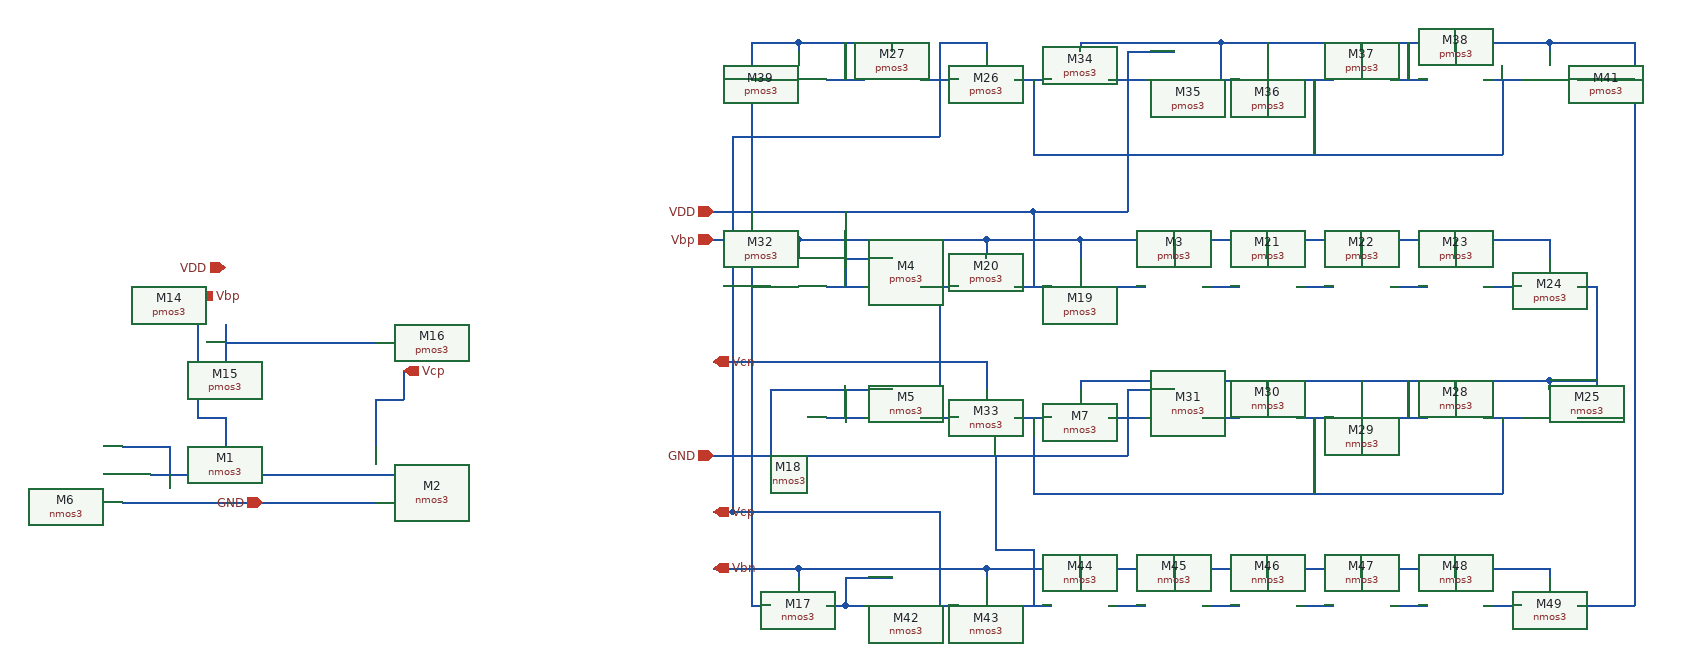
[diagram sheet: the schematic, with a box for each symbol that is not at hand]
v {xschem version=3.4.3 file_version=1.2
}
G {}
K {}
V {}
S {}
E {}
N -270 -190 -180 -190 {
lab=#net1}
N -310 -210 -310 -170 {
lab=#net1}
N -310 -190 -270 -190 {
lab=#net1}
N -340 -240 -340 -140 {
lab=Vbp}
N -340 -140 -340 -110 {
lab=Vbp}
N -340 -110 -310 -110 {
lab=Vbp}
N -120 -160 -120 -130 {
lab=Vcp}
N -150 -130 -120 -130 {
lab=Vcp}
N -180 -190 -150 -190 {
lab=#net1}
N -120 -50 -70 -50 {
lab=Vbn}
N -150 -130 -150 -80 {
lab=Vcp}
N -310 -110 -310 -80 {
lab=Vbp}
N -370 -80 -370 -50 {
lab=Vbn}
N -420 -80 -370 -80 {
lab=Vbn}
N -390 -50 -340 -50 {
lab=Vbn}
N -340 -50 -120 -50 {
lab=Vbn}
N -420 -20 -310 -20 {
lab=GND}
N -310 -20 -270 -20 {
lab=GND}
N -270 -20 -150 -20 {
lab=GND}
N 530 -250 570 -250 {
lab=VDD}
N 550 -310 550 -250 {
lab=VDD}
N 500 -300 500 -280 {
lab=Vbp}
N 500 -300 600 -300 {
lab=Vbp}
N 600 -300 1100 -300 {
lab=Vbp}
N 1100 -300 1100 -280 {
lab=Vbp}
N 1000 -300 1000 -280 {
lab=Vbp}
N 900 -300 900 -280 {
lab=Vbp}
N 800 -300 800 -280 {
lab=Vbp}
N 700 -300 700 -280 {
lab=Vbp}
N 600 -300 600 -280 {
lab=Vbp}
N 1130 -250 1150 -250 {
lab=#net5}
N 800 -150 800 -140 {
lab=#net6}
N 730 -110 770 -110 {
lab=#net7}
N 830 -110 870 -110 {
lab=#net8}
N 900 -150 900 -140 {
lab=#net6}
N 1000 -150 1000 -140 {
lab=#net6}
N 1100 -150 1100 -140 {
lab=#net6}
N 930 -110 970 -110 {
lab=#net9}
N 550 -330 550 -310 {
lab=VDD}
N 210 -330 550 -330 {
lab=VDD}
N 650 -30 1050 -30 {
lab=#net8}
N 630 -250 670 -250 {
lab=#net10}
N 730 -250 770 -250 {
lab=#net11}
N 830 -250 870 -250 {
lab=#net12}
N 930 -250 970 -250 {
lab=#net13}
N 1030 -250 1070 -250 {
lab=#net14}
N 470 -170 500 -170 {
lab=Vcn}
N 210 -170 470 -170 {
lab=Vcn}
N 630 -470 670 -470 {
lab=#net15}
N 730 -470 770 -470 {
lab=#net16}
N 830 -470 870 -470 {
lab=#net15}
N 930 -470 970 -470 {
lab=#net16}
N 1100 -510 1100 -500 {
lab=#net16}
N 1000 -510 1000 -500 {
lab=#net16}
N 900 -510 900 -500 {
lab=#net16}
N 800 -510 800 -500 {
lab=#net16}
N 750 -510 750 -470 {
lab=#net16}
N 950 -510 950 -470 {
lab=#net16}
N 1050 -470 1050 -390 {
lab=#net15}
N 1030 -110 1070 -110 {
lab=#net8}
N 500 -170 500 -140 {
lab=Vcn}
N 430 -250 470 -250 {
lab=Vcn}
N 330 -250 370 -250 {
lab=VDD}
N 350 -330 350 -250 {
lab=VDD}
N 350 60 400 60 {
lab=#net17}
N 350 60 350 90 {
lab=#net17}
N 330 90 350 90 {
lab=#net17}
N 350 90 370 90 {
lab=#net17}
N 350 -280 400 -280 {
lab=VDD}
N 1100 50 1100 60 {
lab=Vbn}
N 500 50 1100 50 {
lab=Vbn}
N 500 50 500 60 {
lab=Vbn}
N 600 50 600 60 {
lab=Vbn}
N 700 50 700 60 {
lab=Vbn}
N 800 50 800 60 {
lab=Vbn}
N 900 50 900 60 {
lab=Vbn}
N 1000 50 1000 60 {
lab=Vbn}
N 530 90 570 90 {
lab=GND}
N 550 30 550 90 {
lab=GND}
N 630 90 670 90 {
lab=#net18}
N 730 90 770 90 {
lab=#net19}
N 830 90 870 90 {
lab=#net20}
N 930 90 970 90 {
lab=#net21}
N 1030 90 1070 90 {
lab=#net22}
N 430 90 470 90 {
lab=Vcp}
N 300 50 300 60 {
lab=Vbn}
N 300 50 500 50 {
lab=Vbn}
N 300 -300 300 -280 {
lab=Vbp}
N 300 -300 500 -300 {
lab=Vbp}
N 270 -300 300 -300 {
lab=Vbp}
N 450 30 450 90 {
lab=Vcp}
N 250 -300 270 -300 {
lab=Vbp}
N 250 -300 250 90 {
lab=Vbp}
N 250 90 270 90 {
lab=Vbp}
N 250 -250 270 -250 {
lab=Vbp}
N 430 -110 470 -110 {
lab=Vcn}
N 270 -140 300 -140 {
lab=GND}
N 270 -140 270 -110 {
lab=GND}
N 270 -110 270 -70 {
lab=GND}
N 330 -110 370 -110 {
lab=GND}
N 350 -140 350 -110 {
lab=GND}
N 1030 -470 1070 -470 {
lab=#net15}
N 530 -470 570 -470 {
lab=Vcp}
N 500 -510 500 -500 {
lab=VDD}
N 300 -510 300 -500 {
lab=VDD}
N 400 -510 400 -500 {
lab=VDD}
N 430 -470 470 -470 {
lab=VDD}
N 330 -470 370 -470 {
lab=VDD}
N 350 -510 350 -470 {
lab=VDD}
N 250 -510 300 -510 {
lab=VDD}
N 250 -510 250 -330 {
lab=VDD}
N 250 -470 270 -470 {
lab=VDD}
N 850 -470 850 -390 {
lab=#net15}
N 1130 90 1190 90 {
lab=#net16}
N 1190 -510 1190 90 {
lab=#net16}
N 1100 -510 1190 -510 {
lab=#net16}
N 210 50 300 50 {
lab=Vbn}
N 210 -300 250 -300 {
lab=Vbp}
N 450 -10 450 30 {
lab=Vcp}
N 230 -10 450 -10 {
lab=Vcp}
N 230 -410 230 -10 {
lab=Vcp}
N 450 -470 450 -410 {
lab=Vcp}
N 210 -10 230 -10 {
lab=Vcp}
N 1130 -110 1150 -110 {
lab=#net23}
N 300 -140 400 -140 {
lab=GND}
N 450 -250 450 -170 {
lab=Vcn}
N 450 -170 450 -110 {
lab=Vcn}
N 530 -110 570 -110 {
lab=#net24}
N 630 -110 670 -110 {
lab=#net25}
N 600 -150 600 -140 {
lab=#net6}
N 650 -140 700 -140 {
lab=#net25}
N 650 -140 650 -110 {
lab=#net25}
N 600 -150 1100 -150 {
lab=#net6}
N 1150 -250 1150 -110 {}
N 1100 -150 1150 -150 {}
N 1050 -110 1050 -30 {}
N 850 -110 850 -30 {}
N 550 -110 550 -30 {}
N 550 -30 650 -30 {}
N 650 -110 650 -70 {}
N 210 -70 650 -70 {}
N 950 -150 950 -110 {}
N 750 -150 750 -110 {}
N 1130 -470 1190 -470 {}
N 230 -410 450 -410 {}
N 300 -510 400 -510 {}
N 450 -510 450 -470 {}
N 450 -510 500 -510 {}
N 750 -510 1100 -510 {}
N 600 -510 600 -500 {}
N 600 -510 750 -510 {}
N 650 -500 700 -500 {}
N 650 -500 650 -470 {}
N 550 -470 550 -390 {}
N 550 -330 650 -330 {}
N 510 30 550 30 {}
N 510 -70 510 30 {}
N 550 -390 1050 -390 {}
N 650 -470 650 -330 {}
C {devices/iopin.sym} -70 -50 0 0 {name=p6 lab=Vbn}
C {devices/iopin.sym} -310 -270 3 0 {name=p2 lab=VDD}
C {devices/iopin.sym} -270 -20 1 0 {name=p3 lab=GND}
C {devices/opin.sym} -340 -240 2 0 {name=p1 lab=Vbp}
C {madvlsi/nmos3.sym} -150 -50 0 0 {name=M2
L=0.5
W=12
body=GND
nf=1
mult=1
ad="'int((nf+1)/2) * W/nf * 0.29'" 
pd="'2*int((nf+1)/2) * (W/nf + 0.29)'"
as="'int((nf+2)/2) * W/nf * 0.29'" 
ps="'2*int((nf+2)/2) * (W/nf + 0.29)'"
nrd="'0.29 / W'" nrs="'0.29 / W'"
sa=0 sb=0 sd=0
model=nfet_01v8
spiceprefix=X
}
C {madvlsi/nmos3.sym} -310 -50 0 0 {name=M1
L=0.5
W=12
body=GND
nf=1
mult=1/5
ad="'int((nf+1)/2) * W/nf * 0.29'" 
pd="'2*int((nf+1)/2) * (W/nf + 0.29)'"
as="'int((nf+2)/2) * W/nf * 0.29'" 
ps="'2*int((nf+2)/2) * (W/nf + 0.29)'"
nrd="'0.29 / W'" nrs="'0.29 / W'"
sa=0 sb=0 sd=0
model=nfet_01v8
spiceprefix=X
}
C {devices/opin.sym} -120 -160 0 0 {name=p7 lab=Vcp}
C {madvlsi/pmos3.sym} -310 -240 0 0 {name=M14
L=0.5
W=12
body=VDD
nf=1
mult=1
ad="'int((nf+1)/2) * W/nf * 0.29'" 
pd="'2*int((nf+1)/2) * (W/nf + 0.29)'"
as="'int((nf+2)/2) * W/nf * 0.29'" 
ps="'2*int((nf+2)/2) * (W/nf + 0.29)'"
nrd="'0.29 / W'" nrs="'0.29 / W'"
sa=0 sb=0 sd=0
model=pfet_01v8
spiceprefix=X
}
C {madvlsi/pmos3.sym} -310 -140 0 0 {name=M15
L=0.5
W=12
body=VDD
nf=1
mult=3
ad="'int((nf+1)/2) * W/nf * 0.29'" 
pd="'2*int((nf+1)/2) * (W/nf + 0.29)'"
as="'int((nf+2)/2) * W/nf * 0.29'" 
ps="'2*int((nf+2)/2) * (W/nf + 0.29)'"
nrd="'0.29 / W'" nrs="'0.29 / W'"
sa=0 sb=0 sd=0
model=pfet_01v8
spiceprefix=X
}
C {madvlsi/pmos3.sym} -150 -160 0 1 {name=M16
L=0.5
W=12
body=VDD
nf=1
mult=1
ad="'int((nf+1)/2) * W/nf * 0.29'" 
pd="'2*int((nf+1)/2) * (W/nf + 0.29)'"
as="'int((nf+2)/2) * W/nf * 0.29'" 
ps="'2*int((nf+2)/2) * (W/nf + 0.29)'"
nrd="'0.29 / W'" nrs="'0.29 / W'"
sa=0 sb=0 sd=0
model=pfet_01v8
spiceprefix=X
}
C {madvlsi/nmos3.sym} -420 -50 0 1 {name=M6
L=0.5
W=12
body=GND
nf=1
mult=1
ad="'int((nf+1)/2) * W/nf * 0.29'" 
pd="'2*int((nf+1)/2) * (W/nf + 0.29)'"
as="'int((nf+2)/2) * W/nf * 0.29'" 
ps="'2*int((nf+2)/2) * (W/nf + 0.29)'"
nrd="'0.29 / W'" nrs="'0.29 / W'"
sa=0 sb=0 sd=0
model=nfet_01v8
spiceprefix=X
}
C {madvlsi/pmos3.sym} 700 -250 1 0 {name=M3
L=0.5
W=12
body=VDD
nf=1
mult=1
ad="'int((nf+1)/2) * W/nf * 0.29'" 
pd="'2*int((nf+1)/2) * (W/nf + 0.29)'"
as="'int((nf+2)/2) * W/nf * 0.29'" 
ps="'2*int((nf+2)/2) * (W/nf + 0.29)'"
nrd="'0.29 / W'" nrs="'0.29 / W'"
sa=0 sb=0 sd=0
model=pfet_01v8
spiceprefix=X
}
C {madvlsi/pmos3.sym} 600 -250 1 0 {name=M19
L=0.5
W=12
body=VDD
nf=1
mult=1
ad="'int((nf+1)/2) * W/nf * 0.29'" 
pd="'2*int((nf+1)/2) * (W/nf + 0.29)'"
as="'int((nf+2)/2) * W/nf * 0.29'" 
ps="'2*int((nf+2)/2) * (W/nf + 0.29)'"
nrd="'0.29 / W'" nrs="'0.29 / W'"
sa=0 sb=0 sd=0
model=pfet_01v8
spiceprefix=X
}
C {madvlsi/pmos3.sym} 500 -250 1 0 {name=M20
L=0.5
W=12
body=VDD
nf=1
mult=1
ad="'int((nf+1)/2) * W/nf * 0.29'" 
pd="'2*int((nf+1)/2) * (W/nf + 0.29)'"
as="'int((nf+2)/2) * W/nf * 0.29'" 
ps="'2*int((nf+2)/2) * (W/nf + 0.29)'"
nrd="'0.29 / W'" nrs="'0.29 / W'"
sa=0 sb=0 sd=0
model=pfet_01v8
spiceprefix=X
}
C {madvlsi/pmos3.sym} 800 -250 1 0 {name=M21
L=0.5
W=12
body=VDD
nf=1
mult=1
ad="'int((nf+1)/2) * W/nf * 0.29'" 
pd="'2*int((nf+1)/2) * (W/nf + 0.29)'"
as="'int((nf+2)/2) * W/nf * 0.29'" 
ps="'2*int((nf+2)/2) * (W/nf + 0.29)'"
nrd="'0.29 / W'" nrs="'0.29 / W'"
sa=0 sb=0 sd=0
model=pfet_01v8
spiceprefix=X
}
C {madvlsi/pmos3.sym} 900 -250 1 0 {name=M22
L=0.5
W=12
body=VDD
nf=1
mult=1
ad="'int((nf+1)/2) * W/nf * 0.29'" 
pd="'2*int((nf+1)/2) * (W/nf + 0.29)'"
as="'int((nf+2)/2) * W/nf * 0.29'" 
ps="'2*int((nf+2)/2) * (W/nf + 0.29)'"
nrd="'0.29 / W'" nrs="'0.29 / W'"
sa=0 sb=0 sd=0
model=pfet_01v8
spiceprefix=X
}
C {madvlsi/pmos3.sym} 1000 -250 1 0 {name=M23
L=0.5
W=12
body=VDD
nf=1
mult=1
ad="'int((nf+1)/2) * W/nf * 0.29'" 
pd="'2*int((nf+1)/2) * (W/nf + 0.29)'"
as="'int((nf+2)/2) * W/nf * 0.29'" 
ps="'2*int((nf+2)/2) * (W/nf + 0.29)'"
nrd="'0.29 / W'" nrs="'0.29 / W'"
sa=0 sb=0 sd=0
model=pfet_01v8
spiceprefix=X
}
C {madvlsi/pmos3.sym} 1100 -250 1 0 {name=M24
L=0.5
W=12
body=VDD
nf=1
mult=1
ad="'int((nf+1)/2) * W/nf * 0.29'" 
pd="'2*int((nf+1)/2) * (W/nf + 0.29)'"
as="'int((nf+2)/2) * W/nf * 0.29'" 
ps="'2*int((nf+2)/2) * (W/nf + 0.29)'"
nrd="'0.29 / W'" nrs="'0.29 / W'"
sa=0 sb=0 sd=0
model=pfet_01v8
spiceprefix=X
}
C {madvlsi/nmos3.sym} 1100 -110 1 0 {name=M25
L=0.5
W=12
body=GND
nf=1
mult=1
ad="'int((nf+1)/2) * W/nf * 0.29'" 
pd="'2*int((nf+1)/2) * (W/nf + 0.29)'"
as="'int((nf+2)/2) * W/nf * 0.29'" 
ps="'2*int((nf+2)/2) * (W/nf + 0.29)'"
nrd="'0.29 / W'" nrs="'0.29 / W'"
sa=0 sb=0 sd=0
model=nfet_01v8
spiceprefix=X
}
C {madvlsi/nmos3.sym} 1000 -110 1 0 {name=M28
L=0.5
W=12
body=GND
nf=1
mult=1
ad="'int((nf+1)/2) * W/nf * 0.29'" 
pd="'2*int((nf+1)/2) * (W/nf + 0.29)'"
as="'int((nf+2)/2) * W/nf * 0.29'" 
ps="'2*int((nf+2)/2) * (W/nf + 0.29)'"
nrd="'0.29 / W'" nrs="'0.29 / W'"
sa=0 sb=0 sd=0
model=nfet_01v8
spiceprefix=X
}
C {madvlsi/nmos3.sym} 900 -110 1 0 {name=M29
L=0.5
W=12
body=GND
nf=1
mult=1
ad="'int((nf+1)/2) * W/nf * 0.29'" 
pd="'2*int((nf+1)/2) * (W/nf + 0.29)'"
as="'int((nf+2)/2) * W/nf * 0.29'" 
ps="'2*int((nf+2)/2) * (W/nf + 0.29)'"
nrd="'0.29 / W'" nrs="'0.29 / W'"
sa=0 sb=0 sd=0
model=nfet_01v8
spiceprefix=X
}
C {madvlsi/nmos3.sym} 800 -110 1 0 {name=M30
L=0.5
W=12
body=GND
nf=1
mult=1
ad="'int((nf+1)/2) * W/nf * 0.29'" 
pd="'2*int((nf+1)/2) * (W/nf + 0.29)'"
as="'int((nf+2)/2) * W/nf * 0.29'" 
ps="'2*int((nf+2)/2) * (W/nf + 0.29)'"
nrd="'0.29 / W'" nrs="'0.29 / W'"
sa=0 sb=0 sd=0
model=nfet_01v8
spiceprefix=X
}
C {madvlsi/nmos3.sym} 700 -110 1 0 {name=M31
L=0.5
W=12
body=GND
nf=1
mult=1
ad="'int((nf+1)/2) * W/nf * 0.29'" 
pd="'2*int((nf+1)/2) * (W/nf + 0.29)'"
as="'int((nf+2)/2) * W/nf * 0.29'" 
ps="'2*int((nf+2)/2) * (W/nf + 0.29)'"
nrd="'0.29 / W'" nrs="'0.29 / W'"
sa=0 sb=0 sd=0
model=nfet_01v8
spiceprefix=X
}
C {devices/iopin.sym} 210 -330 2 0 {name=p8 lab=VDD}
C {madvlsi/pmos3.sym} 300 -250 1 0 {name=M32
L=0.5
W=12
body=VDD
nf=1
mult=1
ad="'int((nf+1)/2) * W/nf * 0.29'" 
pd="'2*int((nf+1)/2) * (W/nf + 0.29)'"
as="'int((nf+2)/2) * W/nf * 0.29'" 
ps="'2*int((nf+2)/2) * (W/nf + 0.29)'"
nrd="'0.29 / W'" nrs="'0.29 / W'"
sa=0 sb=0 sd=0
model=pfet_01v8
spiceprefix=X
}
C {madvlsi/nmos3.sym} 500 -110 1 0 {name=M33
L=0.5
W=12
body=GND
nf=1
mult=1
ad="'int((nf+1)/2) * W/nf * 0.29'" 
pd="'2*int((nf+1)/2) * (W/nf + 0.29)'"
as="'int((nf+2)/2) * W/nf * 0.29'" 
ps="'2*int((nf+2)/2) * (W/nf + 0.29)'"
nrd="'0.29 / W'" nrs="'0.29 / W'"
sa=0 sb=0 sd=0
model=nfet_01v8
spiceprefix=X
}
C {devices/opin.sym} 210 -170 2 0 {name=p9 lab=Vcn}
C {madvlsi/pmos3.sym} 600 -470 1 0 {name=M34
L=0.5
W=12
body=VDD
nf=1
mult=1
ad="'int((nf+1)/2) * W/nf * 0.29'" 
pd="'2*int((nf+1)/2) * (W/nf + 0.29)'"
as="'int((nf+2)/2) * W/nf * 0.29'" 
ps="'2*int((nf+2)/2) * (W/nf + 0.29)'"
nrd="'0.29 / W'" nrs="'0.29 / W'"
sa=0 sb=0 sd=0
model=pfet_01v8
spiceprefix=X
}
C {madvlsi/pmos3.sym} 700 -470 1 0 {name=M35
L=0.5
W=12
body=VDD
nf=1
mult=1
ad="'int((nf+1)/2) * W/nf * 0.29'" 
pd="'2*int((nf+1)/2) * (W/nf + 0.29)'"
as="'int((nf+2)/2) * W/nf * 0.29'" 
ps="'2*int((nf+2)/2) * (W/nf + 0.29)'"
nrd="'0.29 / W'" nrs="'0.29 / W'"
sa=0 sb=0 sd=0
model=pfet_01v8
spiceprefix=X
}
C {madvlsi/pmos3.sym} 800 -470 1 0 {name=M36
L=0.5
W=12
body=VDD
nf=1
mult=1
ad="'int((nf+1)/2) * W/nf * 0.29'" 
pd="'2*int((nf+1)/2) * (W/nf + 0.29)'"
as="'int((nf+2)/2) * W/nf * 0.29'" 
ps="'2*int((nf+2)/2) * (W/nf + 0.29)'"
nrd="'0.29 / W'" nrs="'0.29 / W'"
sa=0 sb=0 sd=0
model=pfet_01v8
spiceprefix=X
}
C {madvlsi/pmos3.sym} 900 -470 1 0 {name=M37
L=0.5
W=12
body=VDD
nf=1
mult=1
ad="'int((nf+1)/2) * W/nf * 0.29'" 
pd="'2*int((nf+1)/2) * (W/nf + 0.29)'"
as="'int((nf+2)/2) * W/nf * 0.29'" 
ps="'2*int((nf+2)/2) * (W/nf + 0.29)'"
nrd="'0.29 / W'" nrs="'0.29 / W'"
sa=0 sb=0 sd=0
model=pfet_01v8
spiceprefix=X
}
C {madvlsi/pmos3.sym} 1000 -470 1 0 {name=M38
L=0.5
W=12
body=VDD
nf=1
mult=1
ad="'int((nf+1)/2) * W/nf * 0.29'" 
pd="'2*int((nf+1)/2) * (W/nf + 0.29)'"
as="'int((nf+2)/2) * W/nf * 0.29'" 
ps="'2*int((nf+2)/2) * (W/nf + 0.29)'"
nrd="'0.29 / W'" nrs="'0.29 / W'"
sa=0 sb=0 sd=0
model=pfet_01v8
spiceprefix=X
}
C {madvlsi/pmos3.sym} 1100 -470 1 0 {name=M41
L=0.5
W=12
body=VDD
nf=1
mult=1
ad="'int((nf+1)/2) * W/nf * 0.29'" 
pd="'2*int((nf+1)/2) * (W/nf + 0.29)'"
as="'int((nf+2)/2) * W/nf * 0.29'" 
ps="'2*int((nf+2)/2) * (W/nf + 0.29)'"
nrd="'0.29 / W'" nrs="'0.29 / W'"
sa=0 sb=0 sd=0
model=pfet_01v8
spiceprefix=X
}
C {madvlsi/nmos3.sym} 400 90 1 0 {name=M42
L=0.5
W=12
body=GND
nf=1
mult=1
ad="'int((nf+1)/2) * W/nf * 0.29'" 
pd="'2*int((nf+1)/2) * (W/nf + 0.29)'"
as="'int((nf+2)/2) * W/nf * 0.29'" 
ps="'2*int((nf+2)/2) * (W/nf + 0.29)'"
nrd="'0.29 / W'" nrs="'0.29 / W'"
sa=0 sb=0 sd=0
model=nfet_01v8
spiceprefix=X
}
C {madvlsi/nmos3.sym} 500 90 1 0 {name=M43
L=0.5
W=12
body=GND
nf=1
mult=1
ad="'int((nf+1)/2) * W/nf * 0.29'" 
pd="'2*int((nf+1)/2) * (W/nf + 0.29)'"
as="'int((nf+2)/2) * W/nf * 0.29'" 
ps="'2*int((nf+2)/2) * (W/nf + 0.29)'"
nrd="'0.29 / W'" nrs="'0.29 / W'"
sa=0 sb=0 sd=0
model=nfet_01v8
spiceprefix=X
}
C {madvlsi/nmos3.sym} 600 90 1 0 {name=M44
L=0.5
W=12
body=GND
nf=1
mult=1
ad="'int((nf+1)/2) * W/nf * 0.29'" 
pd="'2*int((nf+1)/2) * (W/nf + 0.29)'"
as="'int((nf+2)/2) * W/nf * 0.29'" 
ps="'2*int((nf+2)/2) * (W/nf + 0.29)'"
nrd="'0.29 / W'" nrs="'0.29 / W'"
sa=0 sb=0 sd=0
model=nfet_01v8
spiceprefix=X
}
C {madvlsi/nmos3.sym} 700 90 1 0 {name=M45
L=0.5
W=12
body=GND
nf=1
mult=1
ad="'int((nf+1)/2) * W/nf * 0.29'" 
pd="'2*int((nf+1)/2) * (W/nf + 0.29)'"
as="'int((nf+2)/2) * W/nf * 0.29'" 
ps="'2*int((nf+2)/2) * (W/nf + 0.29)'"
nrd="'0.29 / W'" nrs="'0.29 / W'"
sa=0 sb=0 sd=0
model=nfet_01v8
spiceprefix=X
}
C {madvlsi/nmos3.sym} 800 90 1 0 {name=M46
L=0.5
W=12
body=GND
nf=1
mult=1
ad="'int((nf+1)/2) * W/nf * 0.29'" 
pd="'2*int((nf+1)/2) * (W/nf + 0.29)'"
as="'int((nf+2)/2) * W/nf * 0.29'" 
ps="'2*int((nf+2)/2) * (W/nf + 0.29)'"
nrd="'0.29 / W'" nrs="'0.29 / W'"
sa=0 sb=0 sd=0
model=nfet_01v8
spiceprefix=X
}
C {madvlsi/nmos3.sym} 900 90 1 0 {name=M47
L=0.5
W=12
body=GND
nf=1
mult=1
ad="'int((nf+1)/2) * W/nf * 0.29'" 
pd="'2*int((nf+1)/2) * (W/nf + 0.29)'"
as="'int((nf+2)/2) * W/nf * 0.29'" 
ps="'2*int((nf+2)/2) * (W/nf + 0.29)'"
nrd="'0.29 / W'" nrs="'0.29 / W'"
sa=0 sb=0 sd=0
model=nfet_01v8
spiceprefix=X
}
C {madvlsi/nmos3.sym} 1000 90 1 0 {name=M48
L=0.5
W=12
body=GND
nf=1
mult=1
ad="'int((nf+1)/2) * W/nf * 0.29'" 
pd="'2*int((nf+1)/2) * (W/nf + 0.29)'"
as="'int((nf+2)/2) * W/nf * 0.29'" 
ps="'2*int((nf+2)/2) * (W/nf + 0.29)'"
nrd="'0.29 / W'" nrs="'0.29 / W'"
sa=0 sb=0 sd=0
model=nfet_01v8
spiceprefix=X
}
C {madvlsi/nmos3.sym} 1100 90 1 0 {name=M49
L=0.5
W=12
body=GND
nf=1
mult=1
ad="'int((nf+1)/2) * W/nf * 0.29'" 
pd="'2*int((nf+1)/2) * (W/nf + 0.29)'"
as="'int((nf+2)/2) * W/nf * 0.29'" 
ps="'2*int((nf+2)/2) * (W/nf + 0.29)'"
nrd="'0.29 / W'" nrs="'0.29 / W'"
sa=0 sb=0 sd=0
model=nfet_01v8
spiceprefix=X
}
C {devices/iopin.sym} 210 -70 2 0 {name=p4 lab=GND}
C {madvlsi/pmos3.sym} 400 -250 1 0 {name=M4
L=0.5
W=12
body=VDD
nf=1
mult=1
ad="'int((nf+1)/2) * W/nf * 0.29'" 
pd="'2*int((nf+1)/2) * (W/nf + 0.29)'"
as="'int((nf+2)/2) * W/nf * 0.29'" 
ps="'2*int((nf+2)/2) * (W/nf + 0.29)'"
nrd="'0.29 / W'" nrs="'0.29 / W'"
sa=0 sb=0 sd=0
model=pfet_01v8
spiceprefix=X
}
C {madvlsi/nmos3.sym} 300 90 1 0 {name=M17
L=0.5
W=12
body=GND
nf=1
mult=1
ad="'int((nf+1)/2) * W/nf * 0.29'" 
pd="'2*int((nf+1)/2) * (W/nf + 0.29)'"
as="'int((nf+2)/2) * W/nf * 0.29'" 
ps="'2*int((nf+2)/2) * (W/nf + 0.29)'"
nrd="'0.29 / W'" nrs="'0.29 / W'"
sa=0 sb=0 sd=0
model=nfet_01v8
spiceprefix=X
}
C {madvlsi/nmos3.sym} 400 -110 1 0 {name=M5
L=0.5
W=12
body=GND
nf=1
mult=1
ad="'int((nf+1)/2) * W/nf * 0.29'" 
pd="'2*int((nf+1)/2) * (W/nf + 0.29)'"
as="'int((nf+2)/2) * W/nf * 0.29'" 
ps="'2*int((nf+2)/2) * (W/nf + 0.29)'"
nrd="'0.29 / W'" nrs="'0.29 / W'"
sa=0 sb=0 sd=0
model=nfet_01v8
spiceprefix=X
}
C {madvlsi/nmos3.sym} 300 -110 1 0 {name=M18
L=0.5
W=12
body=GND
nf=1
mult=1
ad="'int((nf+1)/2) * W/nf * 0.29'" 
pd="'2*int((nf+1)/2) * (W/nf + 0.29)'"
as="'int((nf+2)/2) * W/nf * 0.29'" 
ps="'2*int((nf+2)/2) * (W/nf + 0.29)'"
nrd="'0.29 / W'" nrs="'0.29 / W'"
sa=0 sb=0 sd=0
model=nfet_01v8
spiceprefix=X
}
C {madvlsi/pmos3.sym} 500 -470 1 0 {name=M26
L=0.5
W=12
body=VDD
nf=1
mult=1
ad="'int((nf+1)/2) * W/nf * 0.29'" 
pd="'2*int((nf+1)/2) * (W/nf + 0.29)'"
as="'int((nf+2)/2) * W/nf * 0.29'" 
ps="'2*int((nf+2)/2) * (W/nf + 0.29)'"
nrd="'0.29 / W'" nrs="'0.29 / W'"
sa=0 sb=0 sd=0
model=pfet_01v8
spiceprefix=X
}
C {madvlsi/pmos3.sym} 400 -470 1 0 {name=M27
L=0.5
W=12
body=VDD
nf=1
mult=1
ad="'int((nf+1)/2) * W/nf * 0.29'" 
pd="'2*int((nf+1)/2) * (W/nf + 0.29)'"
as="'int((nf+2)/2) * W/nf * 0.29'" 
ps="'2*int((nf+2)/2) * (W/nf + 0.29)'"
nrd="'0.29 / W'" nrs="'0.29 / W'"
sa=0 sb=0 sd=0
model=pfet_01v8
spiceprefix=X
}
C {madvlsi/pmos3.sym} 300 -470 1 0 {name=M39
L=0.5
W=12
body=VDD
nf=1
mult=1
ad="'int((nf+1)/2) * W/nf * 0.29'" 
pd="'2*int((nf+1)/2) * (W/nf + 0.29)'"
as="'int((nf+2)/2) * W/nf * 0.29'" 
ps="'2*int((nf+2)/2) * (W/nf + 0.29)'"
nrd="'0.29 / W'" nrs="'0.29 / W'"
sa=0 sb=0 sd=0
model=pfet_01v8
spiceprefix=X
}
C {devices/opin.sym} 210 50 2 0 {name=p10 lab=Vbn}
C {devices/iopin.sym} 210 -300 2 0 {name=p11 lab=Vbp}
C {devices/opin.sym} 210 -10 2 0 {name=p12 lab=Vcp}
C {madvlsi/nmos3.sym} 600 -110 1 0 {name=M7
L=0.5
W=12
body=GND
nf=1
mult=1
ad="'int((nf+1)/2) * W/nf * 0.29'" 
pd="'2*int((nf+1)/2) * (W/nf + 0.29)'"
as="'int((nf+2)/2) * W/nf * 0.29'" 
ps="'2*int((nf+2)/2) * (W/nf + 0.29)'"
nrd="'0.29 / W'" nrs="'0.29 / W'"
sa=0 sb=0 sd=0
model=nfet_01v8
spiceprefix=X
}
